###############################################################
#  Generated by:      Cadence Innovus 21.14-s109_1
#  OS:                Linux x86_64(Host ID caen-vnc-mi11.engin.umich.edu)
#  Generated on:      Sun Apr  2 18:51:28 2023
#  Design:            Main_controller
#  Command:           write_lef_abstract /afs/umich.edu/class/eecs627/w23/groups/group4/CNN_LSTM/Main_controller/apr/controller/data/Main_controller.lef -specifyTopLayer 4 -stripePin -PGpinLayers 4
###############################################################

VERSION 5.8 ;

BUSBITCHARS "[]" ;
DIVIDERCHAR "/" ;

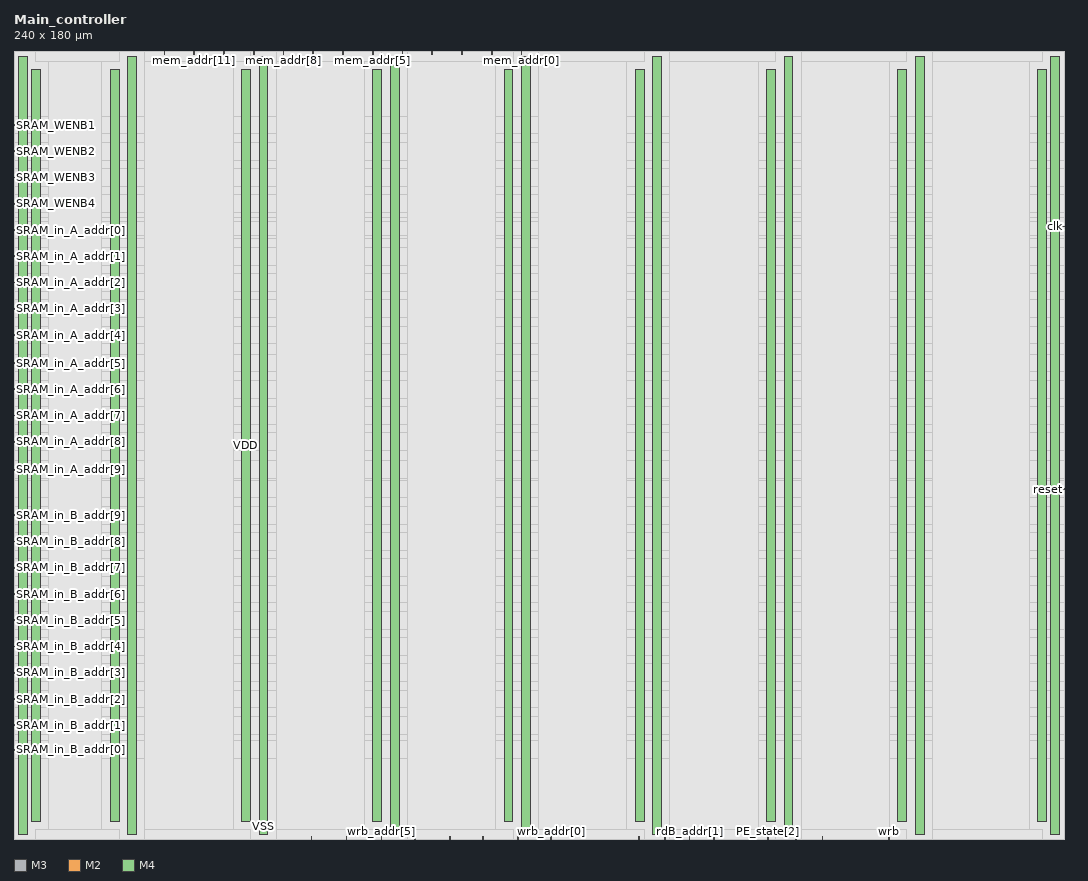
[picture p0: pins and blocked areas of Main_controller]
MACRO Main_controller
  CLASS BLOCK ;
  SIZE 240.000000 BY 180.000000 ;
  FOREIGN Main_controller 0.000000 0.000000 ;
  ORIGIN 0 0 ;
  SYMMETRY X Y R90 ;
  PIN clk
    DIRECTION INPUT ;
    USE SIGNAL ;
    ANTENNAPARTIALMETALAREA 7.46 LAYER M3  ;
    ANTENNAPARTIALMETALSIDEAREA 0.075 LAYER M3  ;
    ANTENNAMODEL OXIDE1 ;
    ANTENNAGATEAREA 0.8352 LAYER M3  ;
    ANTENNAMAXAREACAR 9.44732 LAYER M3  ;
    ANTENNAMAXSIDEAREACAR 0.0952826 LAYER M3  ;
    ANTENNAMAXCUTCAR 0.0957854 LAYER V3  ;
    PORT
      LAYER M3 ;
        RECT 239.400000 139.900000 240.000000 140.100000 ;
    END
  END clk
  PIN reset
    DIRECTION INPUT ;
    USE SIGNAL ;
    ANTENNAPARTIALMETALAREA 27.02 LAYER M3  ;
    ANTENNAPARTIALMETALSIDEAREA 0.2702 LAYER M3  ;
    ANTENNAPARTIALCUTAREA 0.04 LAYER V3  ;
    ANTENNAPARTIALMETALAREA 14.12 LAYER M4  ;
    ANTENNAPARTIALMETALSIDEAREA 0.1416 LAYER M4  ;
    ANTENNAMODEL OXIDE1 ;
    ANTENNAGATEAREA 1.932 LAYER M4  ;
    ANTENNAMAXAREACAR 25.2218 LAYER M4  ;
    ANTENNAMAXSIDEAREACAR 0.252442 LAYER M4  ;
    ANTENNAMAXCUTCAR 1.01838 LAYER V4  ;
    PORT
      LAYER M3 ;
        RECT 239.400000 79.900000 240.000000 80.100000 ;
    END
  END reset
  PIN wrb
    DIRECTION OUTPUT ;
    USE SIGNAL ;
    ANTENNAPARTIALMETALAREA 10.78 LAYER M2  ;
    ANTENNAPARTIALMETALSIDEAREA 0.1078 LAYER M2  ;
    ANTENNAPARTIALCUTAREA 0.08 LAYER V2  ;
    ANTENNAPARTIALMETALAREA 16.12 LAYER M3  ;
    ANTENNAPARTIALMETALSIDEAREA 0.1616 LAYER M3  ;
    ANTENNAPARTIALCUTAREA 0.04 LAYER V3  ;
    ANTENNADIFFAREA 2.014 LAYER M4  ;
    ANTENNAPARTIALMETALAREA 0.84 LAYER M4  ;
    ANTENNAPARTIALMETALSIDEAREA 0.0096 LAYER M4  ;
    ANTENNAMODEL OXIDE1 ;
    ANTENNAGATEAREA 0.2088 LAYER M4  ;
    ANTENNAMAXAREACAR 21.9899 LAYER M4  ;
    ANTENNAMAXSIDEAREACAR 0.229167 LAYER M4  ;
    ANTENNAMAXCUTCAR 2.87356 LAYER V4  ;
    PORT
      LAYER M2 ;
        RECT 199.900000 0.000000 200.100000 0.600000 ;
    END
  END wrb
  PIN PE_state[2]
    DIRECTION OUTPUT ;
    USE SIGNAL ;
    ANTENNAPARTIALMETALAREA 14.22 LAYER M2  ;
    ANTENNAPARTIALMETALSIDEAREA 0.1422 LAYER M2  ;
    ANTENNAPARTIALCUTAREA 0.08 LAYER V2  ;
    ANTENNADIFFAREA 2.172 LAYER M3  ;
    ANTENNAPARTIALMETALAREA 11.24 LAYER M3  ;
    ANTENNAPARTIALMETALSIDEAREA 0.1128 LAYER M3  ;
    PORT
      LAYER M2 ;
        RECT 172.300000 0.000000 172.500000 0.600000 ;
    END
  END PE_state[2]
  PIN PE_state[1]
    DIRECTION OUTPUT ;
    USE SIGNAL ;
    ANTENNAPARTIALMETALAREA 12.46 LAYER M2  ;
    ANTENNAPARTIALMETALSIDEAREA 0.1246 LAYER M2  ;
    ANTENNAPARTIALCUTAREA 0.08 LAYER V2  ;
    ANTENNADIFFAREA 3.196 LAYER M3  ;
    ANTENNAPARTIALMETALAREA 14.52 LAYER M3  ;
    ANTENNAPARTIALMETALSIDEAREA 0.1456 LAYER M3  ;
    PORT
      LAYER M2 ;
        RECT 178.700000 0.000000 178.900000 0.600000 ;
    END
  END PE_state[1]
  PIN PE_state[0]
    DIRECTION OUTPUT ;
    USE SIGNAL ;
    ANTENNAPARTIALMETALAREA 13.26 LAYER M2  ;
    ANTENNAPARTIALMETALSIDEAREA 0.1326 LAYER M2  ;
    ANTENNAPARTIALCUTAREA 0.08 LAYER V2  ;
    ANTENNADIFFAREA 3.378 LAYER M3  ;
    ANTENNAPARTIALMETALAREA 15.48 LAYER M3  ;
    ANTENNAPARTIALMETALSIDEAREA 0.1552 LAYER M3  ;
    PORT
      LAYER M2 ;
        RECT 184.700000 0.000000 184.900000 0.600000 ;
    END
  END PE_state[0]
  PIN wrb_addr[7]
    DIRECTION OUTPUT ;
    USE SIGNAL ;
    ANTENNAPARTIALMETALAREA 4.14 LAYER M2  ;
    ANTENNAPARTIALMETALSIDEAREA 0.0414 LAYER M2  ;
    ANTENNAPARTIALCUTAREA 0.08 LAYER V2  ;
    ANTENNADIFFAREA 2.014 LAYER M3  ;
    ANTENNAPARTIALMETALAREA 4 LAYER M3  ;
    ANTENNAPARTIALMETALSIDEAREA 0.0408 LAYER M3  ;
    ANTENNAMODEL OXIDE1 ;
    ANTENNAGATEAREA 0.4824 LAYER M3  ;
    ANTENNAMAXAREACAR 14.5562 LAYER M3  ;
    ANTENNAMAXSIDEAREACAR 0.153255 LAYER M3  ;
    ANTENNAMAXCUTCAR 1.72414 LAYER V3  ;
    PORT
      LAYER M2 ;
        RECT 67.900000 0.000000 68.100000 0.600000 ;
    END
  END wrb_addr[7]
  PIN wrb_addr[6]
    DIRECTION OUTPUT ;
    USE SIGNAL ;
    ANTENNAPARTIALMETALAREA 2.54 LAYER M2  ;
    ANTENNAPARTIALMETALSIDEAREA 0.0254 LAYER M2  ;
    ANTENNAPARTIALCUTAREA 0.08 LAYER V2  ;
    ANTENNADIFFAREA 2.014 LAYER M3  ;
    ANTENNAPARTIALMETALAREA 2.36 LAYER M3  ;
    ANTENNAPARTIALMETALSIDEAREA 0.024 LAYER M3  ;
    ANTENNAMODEL OXIDE1 ;
    ANTENNAGATEAREA 0.42 LAYER M3  ;
    ANTENNAMAXAREACAR 11.979 LAYER M3  ;
    ANTENNAMAXSIDEAREACAR 0.121749 LAYER M3  ;
    ANTENNAMAXCUTCAR 0.765189 LAYER V3  ;
    PORT
      LAYER M2 ;
        RECT 75.900000 0.000000 76.100000 0.600000 ;
    END
  END wrb_addr[6]
  PIN wrb_addr[5]
    DIRECTION OUTPUT ;
    USE SIGNAL ;
    ANTENNADIFFAREA 2.014 LAYER M2  ;
    ANTENNAPARTIALMETALAREA 4.32 LAYER M2  ;
    ANTENNAPARTIALMETALSIDEAREA 0.0432 LAYER M2  ;
    ANTENNAMODEL OXIDE1 ;
    ANTENNAGATEAREA 0.2136 LAYER M2  ;
    ANTENNAMAXAREACAR 20.7051 LAYER M2  ;
    ANTENNAMAXSIDEAREACAR 0.208333 LAYER M2  ;
    ANTENNAPARTIALCUTAREA 0.16 LAYER V2  ;
    ANTENNAMAXCUTCAR 0.93633 LAYER V2  ;
    ANTENNADIFFAREA 2.014 LAYER M3  ;
    ANTENNAPARTIALMETALAREA 1.52 LAYER M3  ;
    ANTENNAPARTIALMETALSIDEAREA 0.016 LAYER M3  ;
    ANTENNAGATEAREA 0.4464 LAYER M3  ;
    ANTENNAMAXAREACAR 24.1101 LAYER M3  ;
    ANTENNAMAXSIDEAREACAR 0.244176 LAYER M3  ;
    ANTENNAMAXCUTCAR 1.72414 LAYER V3  ;
    PORT
      LAYER M2 ;
        RECT 83.900000 0.000000 84.100000 0.600000 ;
    END
  END wrb_addr[5]
  PIN wrb_addr[4]
    DIRECTION OUTPUT ;
    USE SIGNAL ;
    ANTENNAPARTIALMETALAREA 1.82 LAYER M2  ;
    ANTENNAPARTIALMETALSIDEAREA 0.0182 LAYER M2  ;
    ANTENNAMODEL OXIDE1 ;
    ANTENNAGATEAREA 0.132 LAYER M2  ;
    ANTENNAMAXAREACAR 15.0939 LAYER M2  ;
    ANTENNAMAXSIDEAREACAR 0.151364 LAYER M2  ;
    ANTENNAPARTIALCUTAREA 0.08 LAYER V2  ;
    ANTENNAMAXCUTCAR 0.909091 LAYER V2  ;
    ANTENNAPARTIALMETALAREA 2.48 LAYER M3  ;
    ANTENNAPARTIALMETALSIDEAREA 0.0256 LAYER M3  ;
    ANTENNAGATEAREA 0.2952 LAYER M3  ;
    ANTENNAMAXAREACAR 23.495 LAYER M3  ;
    ANTENNAMAXSIDEAREACAR 0.238085 LAYER M3  ;
    ANTENNAPARTIALCUTAREA 0.08 LAYER V3  ;
    ANTENNAMAXCUTCAR 1.49649 LAYER V3  ;
    ANTENNADIFFAREA 2.014 LAYER M4  ;
    ANTENNAPARTIALMETALAREA 1.24 LAYER M4  ;
    ANTENNAPARTIALMETALSIDEAREA 0.0128 LAYER M4  ;
    ANTENNAGATEAREA 0.5208 LAYER M4  ;
    ANTENNAMAXAREACAR 25.876 LAYER M4  ;
    ANTENNAMAXSIDEAREACAR 0.262662 LAYER M4  ;
    ANTENNAMAXCUTCAR 1.63854 LAYER V4  ;
    PORT
      LAYER M2 ;
        RECT 91.500000 0.000000 91.700000 0.600000 ;
    END
  END wrb_addr[4]
  PIN wrb_addr[3]
    DIRECTION OUTPUT ;
    USE SIGNAL ;
    ANTENNAPARTIALMETALAREA 3.58 LAYER M2  ;
    ANTENNAPARTIALMETALSIDEAREA 0.0358 LAYER M2  ;
    ANTENNAMODEL OXIDE1 ;
    ANTENNAGATEAREA 0.0696 LAYER M2  ;
    ANTENNAMAXAREACAR 53.6782 LAYER M2  ;
    ANTENNAMAXSIDEAREACAR 0.537069 LAYER M2  ;
    ANTENNAPARTIALCUTAREA 0.08 LAYER V2  ;
    ANTENNAMAXCUTCAR 1.72414 LAYER V2  ;
    ANTENNADIFFAREA 2.014 LAYER M3  ;
    ANTENNAPARTIALMETALAREA 2.04 LAYER M3  ;
    ANTENNAPARTIALMETALSIDEAREA 0.0208 LAYER M3  ;
    ANTENNAGATEAREA 0.4152 LAYER M3  ;
    ANTENNAMAXAREACAR 58.5915 LAYER M3  ;
    ANTENNAMAXSIDEAREACAR 0.587165 LAYER M3  ;
    ANTENNAPARTIALCUTAREA 0.08 LAYER V3  ;
    ANTENNAMAXCUTCAR 1.91682 LAYER V3  ;
    ANTENNADIFFAREA 2.014 LAYER M4  ;
    ANTENNAPARTIALMETALAREA 2.44 LAYER M4  ;
    ANTENNAPARTIALMETALSIDEAREA 0.0248 LAYER M4  ;
    ANTENNAGATEAREA 0.684 LAYER M4  ;
    ANTENNAMAXAREACAR 62.1587 LAYER M4  ;
    ANTENNAMAXSIDEAREACAR 0.623423 LAYER M4  ;
    ANTENNAMAXCUTCAR 1.91682 LAYER V4  ;
    PORT
      LAYER M2 ;
        RECT 99.500000 0.000000 99.700000 0.600000 ;
    END
  END wrb_addr[3]
  PIN wrb_addr[2]
    DIRECTION OUTPUT ;
    USE SIGNAL ;
    ANTENNAPARTIALMETALAREA 2.46 LAYER M2  ;
    ANTENNAPARTIALMETALSIDEAREA 0.0246 LAYER M2  ;
    ANTENNAPARTIALCUTAREA 0.08 LAYER V2  ;
    ANTENNADIFFAREA 2.014 LAYER M3  ;
    ANTENNAPARTIALMETALAREA 1.8 LAYER M3  ;
    ANTENNAPARTIALMETALSIDEAREA 0.0184 LAYER M3  ;
    ANTENNAMODEL OXIDE1 ;
    ANTENNAGATEAREA 0.4392 LAYER M3  ;
    ANTENNAMAXAREACAR 14.0163 LAYER M3  ;
    ANTENNAMAXSIDEAREACAR 0.144202 LAYER M3  ;
    ANTENNAMAXCUTCAR 0.857199 LAYER V3  ;
    PORT
      LAYER M2 ;
        RECT 107.100000 0.000000 107.300000 0.600000 ;
    END
  END wrb_addr[2]
  PIN wrb_addr[1]
    DIRECTION OUTPUT ;
    USE SIGNAL ;
    ANTENNAPARTIALMETALAREA 2.7 LAYER M2  ;
    ANTENNAPARTIALMETALSIDEAREA 0.027 LAYER M2  ;
    ANTENNAPARTIALCUTAREA 0.08 LAYER V2  ;
    ANTENNADIFFAREA 2.014 LAYER M3  ;
    ANTENNAPARTIALMETALAREA 2.96 LAYER M3  ;
    ANTENNAPARTIALMETALSIDEAREA 0.0304 LAYER M3  ;
    ANTENNAMODEL OXIDE1 ;
    ANTENNAGATEAREA 0.3336 LAYER M3  ;
    ANTENNAMAXAREACAR 13.3925 LAYER M3  ;
    ANTENNAMAXSIDEAREACAR 0.137809 LAYER M3  ;
    ANTENNAMAXCUTCAR 0.814521 LAYER V3  ;
    PORT
      LAYER M2 ;
        RECT 115.100000 0.000000 115.300000 0.600000 ;
    END
  END wrb_addr[1]
  PIN wrb_addr[0]
    DIRECTION OUTPUT ;
    USE SIGNAL ;
    ANTENNAPARTIALMETALAREA 4.06 LAYER M2  ;
    ANTENNAPARTIALMETALSIDEAREA 0.0406 LAYER M2  ;
    ANTENNAPARTIALCUTAREA 0.08 LAYER V2  ;
    ANTENNADIFFAREA 2.014 LAYER M3  ;
    ANTENNAPARTIALMETALAREA 7.68 LAYER M3  ;
    ANTENNAPARTIALMETALSIDEAREA 0.0776 LAYER M3  ;
    ANTENNAMODEL OXIDE1 ;
    ANTENNAGATEAREA 0.2256 LAYER M3  ;
    ANTENNAMAXAREACAR 52.2724 LAYER M3  ;
    ANTENNAMAXSIDEAREACAR 0.532477 LAYER M3  ;
    ANTENNAPARTIALCUTAREA 0.08 LAYER V3  ;
    ANTENNAMAXCUTCAR 2.65346 LAYER V3  ;
    ANTENNADIFFAREA 2.014 LAYER M4  ;
    ANTENNAPARTIALMETALAREA 0.92 LAYER M4  ;
    ANTENNAPARTIALMETALSIDEAREA 0.0096 LAYER M4  ;
    ANTENNAGATEAREA 0.5616 LAYER M4  ;
    ANTENNAMAXAREACAR 53.9106 LAYER M4  ;
    ANTENNAMAXSIDEAREACAR 0.549571 LAYER M4  ;
    ANTENNAMAXCUTCAR 2.65346 LAYER V4  ;
    PORT
      LAYER M2 ;
        RECT 122.700000 0.000000 122.900000 0.600000 ;
    END
  END wrb_addr[0]
  PIN rdB_addr[3]
    DIRECTION OUTPUT ;
    USE SIGNAL ;
    ANTENNAPARTIALMETALAREA 1.26 LAYER M2  ;
    ANTENNAPARTIALMETALSIDEAREA 0.0126 LAYER M2  ;
    ANTENNAPARTIALCUTAREA 0.08 LAYER V2  ;
    ANTENNADIFFAREA 3.75 LAYER M3  ;
    ANTENNAPARTIALMETALAREA 8 LAYER M3  ;
    ANTENNAPARTIALMETALSIDEAREA 0.0808 LAYER M3  ;
    PORT
      LAYER M2 ;
        RECT 142.700000 0.000000 142.900000 0.600000 ;
    END
  END rdB_addr[3]
  PIN rdB_addr[2]
    DIRECTION OUTPUT ;
    USE SIGNAL ;
    ANTENNAPARTIALMETALAREA 5.74 LAYER M2  ;
    ANTENNAPARTIALMETALSIDEAREA 0.0574 LAYER M2  ;
    ANTENNAPARTIALCUTAREA 0.08 LAYER V2  ;
    ANTENNADIFFAREA 2.56 LAYER M3  ;
    ANTENNAPARTIALMETALAREA 5.48 LAYER M3  ;
    ANTENNAPARTIALMETALSIDEAREA 0.0552 LAYER M3  ;
    PORT
      LAYER M2 ;
        RECT 148.700000 0.000000 148.900000 0.600000 ;
    END
  END rdB_addr[2]
  PIN rdB_addr[1]
    DIRECTION OUTPUT ;
    USE SIGNAL ;
    ANTENNAPARTIALMETALAREA 8.3 LAYER M2  ;
    ANTENNAPARTIALMETALSIDEAREA 0.083 LAYER M2  ;
    ANTENNAPARTIALCUTAREA 0.08 LAYER V2  ;
    ANTENNADIFFAREA 8.58 LAYER M3  ;
    ANTENNAPARTIALMETALAREA 8.16 LAYER M3  ;
    ANTENNAPARTIALMETALSIDEAREA 0.0824 LAYER M3  ;
    ANTENNAMODEL OXIDE1 ;
    ANTENNAGATEAREA 0.4848 LAYER M3  ;
    ANTENNAMAXAREACAR 20.087 LAYER M3  ;
    ANTENNAMAXSIDEAREACAR 0.209418 LAYER M3  ;
    ANTENNAMAXCUTCAR 0.632911 LAYER V3  ;
    PORT
      LAYER M2 ;
        RECT 154.300000 0.000000 154.500000 0.600000 ;
    END
  END rdB_addr[1]
  PIN rdB_addr[0]
    DIRECTION OUTPUT ;
    USE SIGNAL ;
    ANTENNAPARTIALMETALAREA 8.62 LAYER M2  ;
    ANTENNAPARTIALMETALSIDEAREA 0.0862 LAYER M2  ;
    ANTENNAPARTIALCUTAREA 0.08 LAYER V2  ;
    ANTENNADIFFAREA 2.112 LAYER M3  ;
    ANTENNAPARTIALMETALAREA 13.92 LAYER M3  ;
    ANTENNAPARTIALMETALSIDEAREA 0.1408 LAYER M3  ;
    ANTENNAMODEL OXIDE1 ;
    ANTENNAGATEAREA 0.7488 LAYER M3  ;
    ANTENNAMAXAREACAR 46.7611 LAYER M3  ;
    ANTENNAMAXSIDEAREACAR 0.47298 LAYER M3  ;
    ANTENNAMAXCUTCAR 1.34409 LAYER V3  ;
    PORT
      LAYER M2 ;
        RECT 159.900000 0.000000 160.100000 0.600000 ;
    END
  END rdB_addr[0]
  PIN mem_addr[12]
    DIRECTION OUTPUT ;
    USE SIGNAL ;
    ANTENNAPARTIALMETALAREA 1.34 LAYER M2  ;
    ANTENNAPARTIALMETALSIDEAREA 0.0134 LAYER M2  ;
    ANTENNAPARTIALCUTAREA 0.08 LAYER V2  ;
    ANTENNADIFFAREA 2.014 LAYER M3  ;
    ANTENNAPARTIALMETALAREA 1.04 LAYER M3  ;
    ANTENNAPARTIALMETALSIDEAREA 0.0112 LAYER M3  ;
    ANTENNAMODEL OXIDE1 ;
    ANTENNAGATEAREA 0.2016 LAYER M3  ;
    ANTENNAMAXAREACAR 20.3303 LAYER M3  ;
    ANTENNAMAXSIDEAREACAR 0.209715 LAYER M3  ;
    ANTENNAMAXCUTCAR 1.94308 LAYER V3  ;
    PORT
      LAYER M2 ;
        RECT 34.300000 179.400000 34.500000 180.000000 ;
    END
  END mem_addr[12]
  PIN mem_addr[11]
    DIRECTION OUTPUT ;
    USE SIGNAL ;
    ANTENNAPARTIALMETALAREA 4.94 LAYER M2  ;
    ANTENNAPARTIALMETALSIDEAREA 0.0494 LAYER M2  ;
    ANTENNAMODEL OXIDE1 ;
    ANTENNAGATEAREA 0.2016 LAYER M2  ;
    ANTENNAMAXAREACAR 28.366 LAYER M2  ;
    ANTENNAMAXSIDEAREACAR 0.28412 LAYER M2  ;
    ANTENNAPARTIALCUTAREA 0.08 LAYER V2  ;
    ANTENNAMAXCUTCAR 1.54625 LAYER V2  ;
    ANTENNADIFFAREA 2.014 LAYER M3  ;
    ANTENNAPARTIALMETALAREA 0.76 LAYER M3  ;
    ANTENNAPARTIALMETALSIDEAREA 0.008 LAYER M3  ;
    ANTENNAGATEAREA 0.2016 LAYER M3  ;
    ANTENNAMAXAREACAR 32.1359 LAYER M3  ;
    ANTENNAMAXSIDEAREACAR 0.323803 LAYER M3  ;
    ANTENNAMAXCUTCAR 1.54625 LAYER V3  ;
    PORT
      LAYER M2 ;
        RECT 41.100000 179.400000 41.300000 180.000000 ;
    END
  END mem_addr[11]
  PIN mem_addr[10]
    DIRECTION OUTPUT ;
    USE SIGNAL ;
    ANTENNAPARTIALMETALAREA 2.96 LAYER M2  ;
    ANTENNAPARTIALMETALSIDEAREA 0.0296 LAYER M2  ;
    ANTENNAMODEL OXIDE1 ;
    ANTENNAGATEAREA 0.2808 LAYER M2  ;
    ANTENNAMAXAREACAR 12.5393 LAYER M2  ;
    ANTENNAMAXSIDEAREACAR 0.124365 LAYER M2  ;
    ANTENNAPARTIALCUTAREA 0.08 LAYER V2  ;
    ANTENNAMAXCUTCAR 0.822535 LAYER V2  ;
    ANTENNADIFFAREA 2.014 LAYER M3  ;
    ANTENNAPARTIALMETALAREA 0.88 LAYER M3  ;
    ANTENNAPARTIALMETALSIDEAREA 0.0096 LAYER M3  ;
    ANTENNAGATEAREA 0.3504 LAYER M3  ;
    ANTENNAMAXAREACAR 26.4884 LAYER M3  ;
    ANTENNAMAXSIDEAREACAR 0.273374 LAYER M3  ;
    ANTENNAMAXCUTCAR 3.44828 LAYER V3  ;
    PORT
      LAYER M2 ;
        RECT 47.900000 179.400000 48.100000 180.000000 ;
    END
  END mem_addr[10]
  PIN mem_addr[9]
    DIRECTION OUTPUT ;
    USE SIGNAL ;
    ANTENNAPARTIALMETALAREA 4.3 LAYER M2  ;
    ANTENNAPARTIALMETALSIDEAREA 0.043 LAYER M2  ;
    ANTENNAMODEL OXIDE1 ;
    ANTENNAGATEAREA 0.2808 LAYER M2  ;
    ANTENNAMAXAREACAR 17.3114 LAYER M2  ;
    ANTENNAMAXSIDEAREACAR 0.172086 LAYER M2  ;
    ANTENNAPARTIALCUTAREA 0.08 LAYER V2  ;
    ANTENNAMAXCUTCAR 0.822535 LAYER V2  ;
    ANTENNADIFFAREA 2.014 LAYER M3  ;
    ANTENNAPARTIALMETALAREA 1.04 LAYER M3  ;
    ANTENNAPARTIALMETALSIDEAREA 0.0112 LAYER M3  ;
    ANTENNAGATEAREA 0.3504 LAYER M3  ;
    ANTENNAMAXAREACAR 33.8416 LAYER M3  ;
    ANTENNAMAXSIDEAREACAR 0.346906 LAYER M3  ;
    ANTENNAMAXCUTCAR 3.44828 LAYER V3  ;
    PORT
      LAYER M2 ;
        RECT 54.700000 179.400000 54.900000 180.000000 ;
    END
  END mem_addr[9]
  PIN mem_addr[8]
    DIRECTION OUTPUT ;
    USE SIGNAL ;
    ANTENNAPARTIALMETALAREA 1.66 LAYER M2  ;
    ANTENNAPARTIALMETALSIDEAREA 0.0166 LAYER M2  ;
    ANTENNAPARTIALCUTAREA 0.08 LAYER V2  ;
    ANTENNADIFFAREA 2.014 LAYER M3  ;
    ANTENNAPARTIALMETALAREA 2.16 LAYER M3  ;
    ANTENNAPARTIALMETALSIDEAREA 0.0224 LAYER M3  ;
    ANTENNAMODEL OXIDE1 ;
    ANTENNAGATEAREA 0.5808 LAYER M3  ;
    ANTENNAMAXAREACAR 22.1148 LAYER M3  ;
    ANTENNAMAXSIDEAREACAR 0.224186 LAYER M3  ;
    ANTENNAMAXCUTCAR 2.29885 LAYER V3  ;
    PORT
      LAYER M2 ;
        RECT 61.500000 179.400000 61.700000 180.000000 ;
    END
  END mem_addr[8]
  PIN mem_addr[7]
    DIRECTION OUTPUT ;
    USE SIGNAL ;
    ANTENNAPARTIALMETALAREA 2.3 LAYER M2  ;
    ANTENNAPARTIALMETALSIDEAREA 0.023 LAYER M2  ;
    ANTENNAPARTIALCUTAREA 0.08 LAYER V2  ;
    ANTENNADIFFAREA 2.014 LAYER M3  ;
    ANTENNAPARTIALMETALAREA 2.28 LAYER M3  ;
    ANTENNAPARTIALMETALSIDEAREA 0.024 LAYER M3  ;
    ANTENNAMODEL OXIDE1 ;
    ANTENNAGATEAREA 0.3504 LAYER M3  ;
    ANTENNAMAXAREACAR 16.6908 LAYER M3  ;
    ANTENNAMAXSIDEAREACAR 0.176539 LAYER M3  ;
    ANTENNAMAXCUTCAR 3.44828 LAYER V3  ;
    PORT
      LAYER M2 ;
        RECT 68.300000 179.400000 68.500000 180.000000 ;
    END
  END mem_addr[7]
  PIN mem_addr[6]
    DIRECTION OUTPUT ;
    USE SIGNAL ;
    ANTENNAPARTIALMETALAREA 2.38 LAYER M2  ;
    ANTENNAPARTIALMETALSIDEAREA 0.0238 LAYER M2  ;
    ANTENNAPARTIALCUTAREA 0.08 LAYER V2  ;
    ANTENNADIFFAREA 2.014 LAYER M3  ;
    ANTENNAPARTIALMETALAREA 3.8 LAYER M3  ;
    ANTENNAPARTIALMETALSIDEAREA 0.0392 LAYER M3  ;
    ANTENNAMODEL OXIDE1 ;
    ANTENNAGATEAREA 0.4992 LAYER M3  ;
    ANTENNAMAXAREACAR 20.4567 LAYER M3  ;
    ANTENNAMAXSIDEAREACAR 0.20882 LAYER M3  ;
    ANTENNAMAXCUTCAR 2.29885 LAYER V3  ;
    PORT
      LAYER M2 ;
        RECT 75.100000 179.400000 75.300000 180.000000 ;
    END
  END mem_addr[6]
  PIN mem_addr[5]
    DIRECTION OUTPUT ;
    USE SIGNAL ;
    ANTENNAPARTIALMETALAREA 1.98 LAYER M2  ;
    ANTENNAPARTIALMETALSIDEAREA 0.0198 LAYER M2  ;
    ANTENNAMODEL OXIDE1 ;
    ANTENNAGATEAREA 0.1488 LAYER M2  ;
    ANTENNAMAXAREACAR 15.3044 LAYER M2  ;
    ANTENNAMAXSIDEAREACAR 0.152016 LAYER M2  ;
    ANTENNAPARTIALCUTAREA 0.08 LAYER V2  ;
    ANTENNAMAXCUTCAR 1.07527 LAYER V2  ;
    ANTENNADIFFAREA 2.014 LAYER M3  ;
    ANTENNAPARTIALMETALAREA 3.44 LAYER M3  ;
    ANTENNAPARTIALMETALSIDEAREA 0.0352 LAYER M3  ;
    ANTENNAGATEAREA 0.3504 LAYER M3  ;
    ANTENNAMAXAREACAR 47.5875 LAYER M3  ;
    ANTENNAMAXSIDEAREACAR 0.484365 LAYER M3  ;
    ANTENNAMAXCUTCAR 3.44828 LAYER V3  ;
    PORT
      LAYER M2 ;
        RECT 81.900000 179.400000 82.100000 180.000000 ;
    END
  END mem_addr[5]
  PIN mem_addr[4]
    DIRECTION OUTPUT ;
    USE SIGNAL ;
    ANTENNAPARTIALMETALAREA 1.34 LAYER M2  ;
    ANTENNAPARTIALMETALSIDEAREA 0.0134 LAYER M2  ;
    ANTENNAPARTIALCUTAREA 0.08 LAYER V2  ;
    ANTENNADIFFAREA 2.014 LAYER M3  ;
    ANTENNAPARTIALMETALAREA 2.92 LAYER M3  ;
    ANTENNAPARTIALMETALSIDEAREA 0.0304 LAYER M3  ;
    ANTENNAMODEL OXIDE1 ;
    ANTENNAGATEAREA 0.432 LAYER M3  ;
    ANTENNAMAXAREACAR 34.393 LAYER M3  ;
    ANTENNAMAXSIDEAREACAR 0.34994 LAYER M3  ;
    ANTENNAMAXCUTCAR 2.29885 LAYER V3  ;
    PORT
      LAYER M2 ;
        RECT 88.700000 179.400000 88.900000 180.000000 ;
    END
  END mem_addr[4]
  PIN mem_addr[3]
    DIRECTION OUTPUT ;
    USE SIGNAL ;
    ANTENNAPARTIALMETALAREA 1.34 LAYER M2  ;
    ANTENNAPARTIALMETALSIDEAREA 0.0134 LAYER M2  ;
    ANTENNAPARTIALCUTAREA 0.08 LAYER V2  ;
    ANTENNADIFFAREA 2.014 LAYER M3  ;
    ANTENNAPARTIALMETALAREA 1.28 LAYER M3  ;
    ANTENNAPARTIALMETALSIDEAREA 0.0136 LAYER M3  ;
    ANTENNAMODEL OXIDE1 ;
    ANTENNAGATEAREA 0.3504 LAYER M3  ;
    ANTENNAMAXAREACAR 18.0441 LAYER M3  ;
    ANTENNAMAXSIDEAREACAR 0.183121 LAYER M3  ;
    ANTENNAMAXCUTCAR 2.29885 LAYER V3  ;
    PORT
      LAYER M2 ;
        RECT 95.500000 179.400000 95.700000 180.000000 ;
    END
  END mem_addr[3]
  PIN mem_addr[2]
    DIRECTION OUTPUT ;
    USE SIGNAL ;
    ANTENNAPARTIALMETALAREA 1.98 LAYER M2  ;
    ANTENNAPARTIALMETALSIDEAREA 0.0198 LAYER M2  ;
    ANTENNAPARTIALCUTAREA 0.08 LAYER V2  ;
    ANTENNADIFFAREA 2.014 LAYER M3  ;
    ANTENNAPARTIALMETALAREA 2.68 LAYER M3  ;
    ANTENNAPARTIALMETALSIDEAREA 0.028 LAYER M3  ;
    ANTENNAMODEL OXIDE1 ;
    ANTENNAGATEAREA 0.4992 LAYER M3  ;
    ANTENNAMAXAREACAR 32.7939 LAYER M3  ;
    ANTENNAMAXSIDEAREACAR 0.33655 LAYER M3  ;
    ANTENNAMAXCUTCAR 3.44828 LAYER V3  ;
    PORT
      LAYER M2 ;
        RECT 102.300000 179.400000 102.500000 180.000000 ;
    END
  END mem_addr[2]
  PIN mem_addr[1]
    DIRECTION OUTPUT ;
    USE SIGNAL ;
    ANTENNAPARTIALMETALAREA 2.3 LAYER M2  ;
    ANTENNAPARTIALMETALSIDEAREA 0.023 LAYER M2  ;
    ANTENNAMODEL OXIDE1 ;
    ANTENNAGATEAREA 0.1488 LAYER M2  ;
    ANTENNAMAXAREACAR 16.4778 LAYER M2  ;
    ANTENNAMAXSIDEAREACAR 0.165323 LAYER M2  ;
    ANTENNAPARTIALCUTAREA 0.08 LAYER V2  ;
    ANTENNAMAXCUTCAR 0.806452 LAYER V2  ;
    ANTENNADIFFAREA 2.014 LAYER M3  ;
    ANTENNAPARTIALMETALAREA 2.08 LAYER M3  ;
    ANTENNAPARTIALMETALSIDEAREA 0.0216 LAYER M3  ;
    ANTENNAGATEAREA 0.3504 LAYER M3  ;
    ANTENNAMAXAREACAR 36.8096 LAYER M3  ;
    ANTENNAMAXSIDEAREACAR 0.376586 LAYER M3  ;
    ANTENNAMAXCUTCAR 3.44828 LAYER V3  ;
    PORT
      LAYER M2 ;
        RECT 109.100000 179.400000 109.300000 180.000000 ;
    END
  END mem_addr[1]
  PIN mem_addr[0]
    DIRECTION OUTPUT ;
    USE SIGNAL ;
    ANTENNAPARTIALMETALAREA 1.66 LAYER M2  ;
    ANTENNAPARTIALMETALSIDEAREA 0.0166 LAYER M2  ;
    ANTENNAPARTIALCUTAREA 0.08 LAYER V2  ;
    ANTENNAPARTIALMETALAREA 2.04 LAYER M3  ;
    ANTENNAPARTIALMETALSIDEAREA 0.0208 LAYER M3  ;
    ANTENNAMODEL OXIDE1 ;
    ANTENNAGATEAREA 0.1488 LAYER M3  ;
    ANTENNAMAXAREACAR 17.5894 LAYER M3  ;
    ANTENNAMAXSIDEAREACAR 0.180242 LAYER M3  ;
    ANTENNAPARTIALCUTAREA 0.08 LAYER V3  ;
    ANTENNAMAXCUTCAR 1.6129 LAYER V3  ;
    ANTENNADIFFAREA 2.014 LAYER M4  ;
    ANTENNAPARTIALMETALAREA 3.48 LAYER M4  ;
    ANTENNAPARTIALMETALSIDEAREA 0.0352 LAYER M4  ;
    ANTENNAGATEAREA 0.504 LAYER M4  ;
    ANTENNAMAXAREACAR 24.4941 LAYER M4  ;
    ANTENNAMAXSIDEAREACAR 0.250083 LAYER M4  ;
    ANTENNAMAXCUTCAR 2.52408 LAYER V4  ;
    PORT
      LAYER M2 ;
        RECT 115.900000 179.400000 116.100000 180.000000 ;
    END
  END mem_addr[0]
  PIN SRAM_in_A_addr[9]
    DIRECTION OUTPUT ;
    USE SIGNAL ;
    ANTENNADIFFAREA 2.014 LAYER M3  ;
    ANTENNAPARTIALMETALAREA 9.02 LAYER M3  ;
    ANTENNAPARTIALMETALSIDEAREA 0.0918 LAYER M3  ;
    ANTENNAMODEL OXIDE1 ;
    ANTENNAGATEAREA 0.6648 LAYER M3  ;
    ANTENNAMAXAREACAR 32.6225 LAYER M3  ;
    ANTENNAMAXSIDEAREACAR 0.330814 LAYER M3  ;
    ANTENNAMAXCUTCAR 2.12121 LAYER V3  ;
    PORT
      LAYER M3 ;
        RECT 0.000000 84.300000 0.600000 84.500000 ;
    END
  END SRAM_in_A_addr[9]
  PIN SRAM_in_A_addr[8]
    DIRECTION OUTPUT ;
    USE SIGNAL ;
    ANTENNADIFFAREA 2.014 LAYER M3  ;
    ANTENNAPARTIALMETALAREA 9.22 LAYER M3  ;
    ANTENNAPARTIALMETALSIDEAREA 0.0934 LAYER M3  ;
    ANTENNAMODEL OXIDE1 ;
    ANTENNAGATEAREA 0.6144 LAYER M3  ;
    ANTENNAMAXAREACAR 27.3121 LAYER M3  ;
    ANTENNAMAXSIDEAREACAR 0.272852 LAYER M3  ;
    ANTENNAMAXCUTCAR 1.14943 LAYER V3  ;
    PORT
      LAYER M3 ;
        RECT 0.000000 90.700000 0.600000 90.900000 ;
    END
  END SRAM_in_A_addr[8]
  PIN SRAM_in_A_addr[7]
    DIRECTION OUTPUT ;
    USE SIGNAL ;
    ANTENNAPARTIALMETALAREA 12.06 LAYER M3  ;
    ANTENNAPARTIALMETALSIDEAREA 0.1206 LAYER M3  ;
    ANTENNAMODEL OXIDE1 ;
    ANTENNAGATEAREA 0.4752 LAYER M3  ;
    ANTENNAMAXAREACAR 30.8714 LAYER M3  ;
    ANTENNAMAXSIDEAREACAR 0.310374 LAYER M3  ;
    ANTENNAPARTIALCUTAREA 0.08 LAYER V3  ;
    ANTENNAMAXCUTCAR 1.24362 LAYER V3  ;
    ANTENNADIFFAREA 4.168 LAYER M4  ;
    ANTENNAPARTIALMETALAREA 3.64 LAYER M4  ;
    ANTENNAPARTIALMETALSIDEAREA 0.0368 LAYER M4  ;
    ANTENNAGATEAREA 1.3176 LAYER M4  ;
    ANTENNAMAXAREACAR 33.634 LAYER M4  ;
    ANTENNAMAXSIDEAREACAR 0.338303 LAYER M4  ;
    ANTENNAMAXCUTCAR 1.53568 LAYER V4  ;
    PORT
      LAYER M3 ;
        RECT 0.000000 96.700000 0.600000 96.900000 ;
    END
  END SRAM_in_A_addr[7]
  PIN SRAM_in_A_addr[6]
    DIRECTION OUTPUT ;
    USE SIGNAL ;
    ANTENNAPARTIALMETALAREA 4.94 LAYER M3  ;
    ANTENNAPARTIALMETALSIDEAREA 0.0494 LAYER M3  ;
    ANTENNAPARTIALCUTAREA 0.08 LAYER V3  ;
    ANTENNADIFFAREA 4.168 LAYER M4  ;
    ANTENNAPARTIALMETALAREA 3.36 LAYER M4  ;
    ANTENNAPARTIALMETALSIDEAREA 0.0344 LAYER M4  ;
    ANTENNAMODEL OXIDE1 ;
    ANTENNAGATEAREA 1.4304 LAYER M4  ;
    ANTENNAMAXAREACAR 45.6146 LAYER M4  ;
    ANTENNAMAXSIDEAREACAR 0.464998 LAYER M4  ;
    ANTENNAMAXCUTCAR 2.9639 LAYER V4  ;
    PORT
      LAYER M3 ;
        RECT 0.000000 102.700000 0.600000 102.900000 ;
    END
  END SRAM_in_A_addr[6]
  PIN SRAM_in_A_addr[5]
    DIRECTION OUTPUT ;
    USE SIGNAL ;
    ANTENNAPARTIALMETALAREA 5.66 LAYER M3  ;
    ANTENNAPARTIALMETALSIDEAREA 0.0566 LAYER M3  ;
    ANTENNAPARTIALCUTAREA 0.08 LAYER V3  ;
    ANTENNADIFFAREA 3.996 LAYER M4  ;
    ANTENNAPARTIALMETALAREA 10.16 LAYER M4  ;
    ANTENNAPARTIALMETALSIDEAREA 0.1024 LAYER M4  ;
    ANTENNAMODEL OXIDE1 ;
    ANTENNAGATEAREA 2.0616 LAYER M4  ;
    ANTENNAMAXAREACAR 29.8738 LAYER M4  ;
    ANTENNAMAXSIDEAREACAR 0.307735 LAYER M4  ;
    ANTENNAMAXCUTCAR 1.96078 LAYER V4  ;
    PORT
      LAYER M3 ;
        RECT 0.000000 108.700000 0.600000 108.900000 ;
    END
  END SRAM_in_A_addr[5]
  PIN SRAM_in_A_addr[4]
    DIRECTION OUTPUT ;
    USE SIGNAL ;
    ANTENNADIFFAREA 2.014 LAYER M3  ;
    ANTENNAPARTIALMETALAREA 11.9 LAYER M3  ;
    ANTENNAPARTIALMETALSIDEAREA 0.119 LAYER M3  ;
    ANTENNAMODEL OXIDE1 ;
    ANTENNAGATEAREA 0.54 LAYER M3  ;
    ANTENNAMAXAREACAR 29.4508 LAYER M3  ;
    ANTENNAMAXSIDEAREACAR 0.300543 LAYER M3  ;
    ANTENNAMAXCUTCAR 1.72414 LAYER V3  ;
    PORT
      LAYER M3 ;
        RECT 0.000000 115.100000 0.600000 115.300000 ;
    END
  END SRAM_in_A_addr[4]
  PIN SRAM_in_A_addr[3]
    DIRECTION OUTPUT ;
    USE SIGNAL ;
    ANTENNADIFFAREA 4.168 LAYER M3  ;
    ANTENNAPARTIALMETALAREA 14.34 LAYER M3  ;
    ANTENNAPARTIALMETALSIDEAREA 0.1438 LAYER M3  ;
    ANTENNAMODEL OXIDE1 ;
    ANTENNAGATEAREA 0.624 LAYER M3  ;
    ANTENNAMAXAREACAR 30.3946 LAYER M3  ;
    ANTENNAMAXSIDEAREACAR 0.310621 LAYER M3  ;
    ANTENNAPARTIALCUTAREA 0.08 LAYER V3  ;
    ANTENNAMAXCUTCAR 1.85234 LAYER V3  ;
    ANTENNADIFFAREA 4.168 LAYER M4  ;
    ANTENNAPARTIALMETALAREA 0.76 LAYER M4  ;
    ANTENNAPARTIALMETALSIDEAREA 0.008 LAYER M4  ;
    ANTENNAGATEAREA 0.7824 LAYER M4  ;
    ANTENNAMAXAREACAR 31.3659 LAYER M4  ;
    ANTENNAMAXSIDEAREACAR 0.320846 LAYER M4  ;
    ANTENNAMAXCUTCAR 1.85234 LAYER V4  ;
    PORT
      LAYER M3 ;
        RECT 0.000000 121.100000 0.600000 121.300000 ;
    END
  END SRAM_in_A_addr[3]
  PIN SRAM_in_A_addr[2]
    DIRECTION OUTPUT ;
    USE SIGNAL ;
    ANTENNADIFFAREA 4.168 LAYER M3  ;
    ANTENNAPARTIALMETALAREA 14.9 LAYER M3  ;
    ANTENNAPARTIALMETALSIDEAREA 0.1502 LAYER M3  ;
    ANTENNAMODEL OXIDE1 ;
    ANTENNAGATEAREA 0.9312 LAYER M3  ;
    ANTENNAMAXAREACAR 23.1379 LAYER M3  ;
    ANTENNAMAXSIDEAREACAR 0.236171 LAYER M3  ;
    ANTENNAPARTIALCUTAREA 0.08 LAYER V3  ;
    ANTENNAMAXCUTCAR 2.00899 LAYER V3  ;
    ANTENNADIFFAREA 4.168 LAYER M4  ;
    ANTENNAPARTIALMETALAREA 9.64 LAYER M4  ;
    ANTENNAPARTIALMETALSIDEAREA 0.0968 LAYER M4  ;
    ANTENNAGATEAREA 1.2192 LAYER M4  ;
    ANTENNAMAXAREACAR 31.0447 LAYER M4  ;
    ANTENNAMAXSIDEAREACAR 0.315567 LAYER M4  ;
    ANTENNAMAXCUTCAR 2.65873 LAYER V4  ;
    PORT
      LAYER M3 ;
        RECT 0.000000 127.100000 0.600000 127.300000 ;
    END
  END SRAM_in_A_addr[2]
  PIN SRAM_in_A_addr[1]
    DIRECTION OUTPUT ;
    USE SIGNAL ;
    ANTENNADIFFAREA 4.168 LAYER M3  ;
    ANTENNAPARTIALMETALAREA 12.36 LAYER M3  ;
    ANTENNAPARTIALMETALSIDEAREA 0.124 LAYER M3  ;
    ANTENNAMODEL OXIDE1 ;
    ANTENNAGATEAREA 0.3912 LAYER M3  ;
    ANTENNAMAXAREACAR 42.5277 LAYER M3  ;
    ANTENNAMAXSIDEAREACAR 0.427609 LAYER M3  ;
    ANTENNAPARTIALCUTAREA 0.08 LAYER V3  ;
    ANTENNAMAXCUTCAR 0.983711 LAYER V3  ;
    ANTENNADIFFAREA 4.168 LAYER M4  ;
    ANTENNAPARTIALMETALAREA 2.24 LAYER M4  ;
    ANTENNAPARTIALMETALSIDEAREA 0.0232 LAYER M4  ;
    ANTENNAGATEAREA 1.3512 LAYER M4  ;
    ANTENNAMAXAREACAR 44.1855 LAYER M4  ;
    ANTENNAMAXSIDEAREACAR 0.444779 LAYER M4  ;
    ANTENNAMAXCUTCAR 1.46248 LAYER V4  ;
    PORT
      LAYER M3 ;
        RECT 0.000000 133.100000 0.600000 133.300000 ;
    END
  END SRAM_in_A_addr[1]
  PIN SRAM_in_A_addr[0]
    DIRECTION OUTPUT ;
    USE SIGNAL ;
    ANTENNAPARTIALMETALAREA 8.26 LAYER M3  ;
    ANTENNAPARTIALMETALSIDEAREA 0.083 LAYER M3  ;
    ANTENNAMODEL OXIDE1 ;
    ANTENNAGATEAREA 0.3216 LAYER M3  ;
    ANTENNAMAXAREACAR 31.8917 LAYER M3  ;
    ANTENNAMAXSIDEAREACAR 0.316867 LAYER M3  ;
    ANTENNAPARTIALCUTAREA 0.04 LAYER V3  ;
    ANTENNAMAXCUTCAR 0.641952 LAYER V3  ;
    ANTENNADIFFAREA 4.168 LAYER M4  ;
    ANTENNAPARTIALMETALAREA 5.24 LAYER M4  ;
    ANTENNAPARTIALMETALSIDEAREA 0.0528 LAYER M4  ;
    ANTENNAGATEAREA 1.2504 LAYER M4  ;
    ANTENNAMAXAREACAR 36.0823 LAYER M4  ;
    ANTENNAMAXSIDEAREACAR 0.359094 LAYER M4  ;
    ANTENNAMAXCUTCAR 1.31444 LAYER V4  ;
    PORT
      LAYER M3 ;
        RECT 0.000000 139.100000 0.600000 139.300000 ;
    END
  END SRAM_in_A_addr[0]
  PIN SRAM_in_B_addr[9]
    DIRECTION OUTPUT ;
    USE SIGNAL ;
    ANTENNAPARTIALMETALAREA 4.9 LAYER M3  ;
    ANTENNAPARTIALMETALSIDEAREA 0.0494 LAYER M3  ;
    ANTENNAMODEL OXIDE1 ;
    ANTENNAGATEAREA 0.5208 LAYER M3  ;
    ANTENNAMAXAREACAR 18.2374 LAYER M3  ;
    ANTENNAMAXSIDEAREACAR 0.180612 LAYER M3  ;
    ANTENNAPARTIALCUTAREA 0.08 LAYER V3  ;
    ANTENNAMAXCUTCAR 1.69207 LAYER V3  ;
    ANTENNADIFFAREA 2.014 LAYER M4  ;
    ANTENNAPARTIALMETALAREA 1.4 LAYER M4  ;
    ANTENNAPARTIALMETALSIDEAREA 0.0144 LAYER M4  ;
    ANTENNAGATEAREA 0.8016 LAYER M4  ;
    ANTENNAMAXAREACAR 19.9839 LAYER M4  ;
    ANTENNAMAXSIDEAREACAR 0.198576 LAYER M4  ;
    ANTENNAMAXCUTCAR 1.69207 LAYER V4  ;
    PORT
      LAYER M3 ;
        RECT 0.000000 73.900000 0.600000 74.100000 ;
    END
  END SRAM_in_B_addr[9]
  PIN SRAM_in_B_addr[8]
    DIRECTION OUTPUT ;
    USE SIGNAL ;
    ANTENNAPARTIALMETALAREA 4.86 LAYER M3  ;
    ANTENNAPARTIALMETALSIDEAREA 0.0486 LAYER M3  ;
    ANTENNAMODEL OXIDE1 ;
    ANTENNAGATEAREA 0.2328 LAYER M3  ;
    ANTENNAMAXAREACAR 27.4328 LAYER M3  ;
    ANTENNAMAXSIDEAREACAR 0.276357 LAYER M3  ;
    ANTENNAPARTIALCUTAREA 0.08 LAYER V3  ;
    ANTENNAMAXCUTCAR 1.46248 LAYER V3  ;
    ANTENNADIFFAREA 2.014 LAYER M4  ;
    ANTENNAPARTIALMETALAREA 2.2 LAYER M4  ;
    ANTENNAPARTIALMETALSIDEAREA 0.0224 LAYER M4  ;
    ANTENNAGATEAREA 0.5976 LAYER M4  ;
    ANTENNAMAXAREACAR 31.1142 LAYER M4  ;
    ANTENNAMAXSIDEAREACAR 0.31384 LAYER M4  ;
    ANTENNAMAXCUTCAR 1.94344 LAYER V4  ;
    PORT
      LAYER M3 ;
        RECT 0.000000 67.900000 0.600000 68.100000 ;
    END
  END SRAM_in_B_addr[8]
  PIN SRAM_in_B_addr[7]
    DIRECTION OUTPUT ;
    USE SIGNAL ;
    ANTENNADIFFAREA 2.014 LAYER M3  ;
    ANTENNAPARTIALMETALAREA 5.22 LAYER M3  ;
    ANTENNAPARTIALMETALSIDEAREA 0.0526 LAYER M3  ;
    ANTENNAMODEL OXIDE1 ;
    ANTENNAGATEAREA 0.6528 LAYER M3  ;
    ANTENNAMAXAREACAR 20.3543 LAYER M3  ;
    ANTENNAMAXSIDEAREACAR 0.208662 LAYER M3  ;
    ANTENNAPARTIALCUTAREA 0.08 LAYER V3  ;
    ANTENNAMAXCUTCAR 1.6377 LAYER V3  ;
    ANTENNADIFFAREA 2.014 LAYER M4  ;
    ANTENNAPARTIALMETALAREA 1 LAYER M4  ;
    ANTENNAPARTIALMETALSIDEAREA 0.0104 LAYER M4  ;
    ANTENNAGATEAREA 0.7224 LAYER M4  ;
    ANTENNAMAXAREACAR 21.7386 LAYER M4  ;
    ANTENNAMAXSIDEAREACAR 0.223059 LAYER M4  ;
    ANTENNAMAXCUTCAR 3.44828 LAYER V4  ;
    PORT
      LAYER M3 ;
        RECT 0.000000 61.900000 0.600000 62.100000 ;
    END
  END SRAM_in_B_addr[7]
  PIN SRAM_in_B_addr[6]
    DIRECTION OUTPUT ;
    USE SIGNAL ;
    ANTENNADIFFAREA 2.014 LAYER M3  ;
    ANTENNAPARTIALMETALAREA 7.42 LAYER M3  ;
    ANTENNAPARTIALMETALSIDEAREA 0.075 LAYER M3  ;
    ANTENNAMODEL OXIDE1 ;
    ANTENNAGATEAREA 0.6816 LAYER M3  ;
    ANTENNAMAXAREACAR 19.5212 LAYER M3  ;
    ANTENNAMAXSIDEAREACAR 0.202229 LAYER M3  ;
    ANTENNAMAXCUTCAR 2.29885 LAYER V3  ;
    PORT
      LAYER M3 ;
        RECT 0.000000 55.900000 0.600000 56.100000 ;
    END
  END SRAM_in_B_addr[6]
  PIN SRAM_in_B_addr[5]
    DIRECTION OUTPUT ;
    USE SIGNAL ;
    ANTENNAPARTIALMETALAREA 5.3 LAYER M3  ;
    ANTENNAPARTIALMETALSIDEAREA 0.0534 LAYER M3  ;
    ANTENNAMODEL OXIDE1 ;
    ANTENNAGATEAREA 0.5208 LAYER M3  ;
    ANTENNAMAXAREACAR 26.6761 LAYER M3  ;
    ANTENNAMAXSIDEAREACAR 0.26982 LAYER M3  ;
    ANTENNAPARTIALCUTAREA 0.08 LAYER V3  ;
    ANTENNAMAXCUTCAR 2.03564 LAYER V3  ;
    ANTENNADIFFAREA 2.014 LAYER M4  ;
    ANTENNAPARTIALMETALAREA 0.76 LAYER M4  ;
    ANTENNAPARTIALMETALSIDEAREA 0.008 LAYER M4  ;
    ANTENNAGATEAREA 0.6504 LAYER M4  ;
    ANTENNAMAXAREACAR 27.8446 LAYER M4  ;
    ANTENNAMAXSIDEAREACAR 0.28212 LAYER M4  ;
    ANTENNAMAXCUTCAR 2.16049 LAYER V4  ;
    PORT
      LAYER M3 ;
        RECT 0.000000 49.900000 0.600000 50.100000 ;
    END
  END SRAM_in_B_addr[5]
  PIN SRAM_in_B_addr[4]
    DIRECTION OUTPUT ;
    USE SIGNAL ;
    ANTENNADIFFAREA 2.014 LAYER M3  ;
    ANTENNAPARTIALMETALAREA 5.42 LAYER M3  ;
    ANTENNAPARTIALMETALSIDEAREA 0.055 LAYER M3  ;
    ANTENNAMODEL OXIDE1 ;
    ANTENNAGATEAREA 0.5064 LAYER M3  ;
    ANTENNAMAXAREACAR 23.1858 LAYER M3  ;
    ANTENNAMAXSIDEAREACAR 0.239644 LAYER M3  ;
    ANTENNAMAXCUTCAR 2.29885 LAYER V3  ;
    PORT
      LAYER M3 ;
        RECT 0.000000 43.900000 0.600000 44.100000 ;
    END
  END SRAM_in_B_addr[4]
  PIN SRAM_in_B_addr[3]
    DIRECTION OUTPUT ;
    USE SIGNAL ;
    ANTENNADIFFAREA 2.014 LAYER M3  ;
    ANTENNAPARTIALMETALAREA 6.06 LAYER M3  ;
    ANTENNAPARTIALMETALSIDEAREA 0.0614 LAYER M3  ;
    ANTENNAMODEL OXIDE1 ;
    ANTENNAGATEAREA 0.4272 LAYER M3  ;
    ANTENNAMAXAREACAR 20.921 LAYER M3  ;
    ANTENNAMAXSIDEAREACAR 0.21729 LAYER M3  ;
    ANTENNAMAXCUTCAR 2.29885 LAYER V3  ;
    PORT
      LAYER M3 ;
        RECT 0.000000 37.900000 0.600000 38.100000 ;
    END
  END SRAM_in_B_addr[3]
  PIN SRAM_in_B_addr[2]
    DIRECTION OUTPUT ;
    USE SIGNAL ;
    ANTENNADIFFAREA 2.014 LAYER M3  ;
    ANTENNAPARTIALMETALAREA 5.02 LAYER M3  ;
    ANTENNAPARTIALMETALSIDEAREA 0.051 LAYER M3  ;
    ANTENNAMODEL OXIDE1 ;
    ANTENNAGATEAREA 1.0968 LAYER M3  ;
    ANTENNAMAXAREACAR 29.7034 LAYER M3  ;
    ANTENNAMAXSIDEAREACAR 0.30397 LAYER M3  ;
    ANTENNAMAXCUTCAR 3.44828 LAYER V3  ;
    PORT
      LAYER M3 ;
        RECT 0.000000 31.900000 0.600000 32.100000 ;
    END
  END SRAM_in_B_addr[2]
  PIN SRAM_in_B_addr[1]
    DIRECTION OUTPUT ;
    USE SIGNAL ;
    ANTENNADIFFAREA 2.014 LAYER M3  ;
    ANTENNAPARTIALMETALAREA 5.98 LAYER M3  ;
    ANTENNAPARTIALMETALSIDEAREA 0.0606 LAYER M3  ;
    ANTENNAMODEL OXIDE1 ;
    ANTENNAGATEAREA 1.056 LAYER M3  ;
    ANTENNAMAXAREACAR 18.3212 LAYER M3  ;
    ANTENNAMAXSIDEAREACAR 0.185973 LAYER M3  ;
    ANTENNAMAXCUTCAR 1.76671 LAYER V3  ;
    PORT
      LAYER M3 ;
        RECT 0.000000 25.900000 0.600000 26.100000 ;
    END
  END SRAM_in_B_addr[1]
  PIN SRAM_in_B_addr[0]
    DIRECTION OUTPUT ;
    USE SIGNAL ;
    ANTENNADIFFAREA 3.488 LAYER M3  ;
    ANTENNAPARTIALMETALAREA 11.26 LAYER M3  ;
    ANTENNAPARTIALMETALSIDEAREA 0.1134 LAYER M3  ;
    ANTENNAMODEL OXIDE1 ;
    ANTENNAGATEAREA 1.2096 LAYER M3  ;
    ANTENNAMAXAREACAR 44.4371 LAYER M3  ;
    ANTENNAMAXSIDEAREACAR 0.452083 LAYER M3  ;
    ANTENNAMAXCUTCAR 3.20513 LAYER V3  ;
    PORT
      LAYER M3 ;
        RECT 0.000000 20.300000 0.600000 20.500000 ;
    END
  END SRAM_in_B_addr[0]
  PIN SRAM_WENB1
    DIRECTION OUTPUT ;
    USE SIGNAL ;
    ANTENNAPARTIALMETALAREA 5.3 LAYER M3  ;
    ANTENNAPARTIALMETALSIDEAREA 0.0534 LAYER M3  ;
    ANTENNAMODEL OXIDE1 ;
    ANTENNAGATEAREA 0.1728 LAYER M3  ;
    ANTENNAMAXAREACAR 32.588 LAYER M3  ;
    ANTENNAMAXSIDEAREACAR 0.33125 LAYER M3  ;
    ANTENNAPARTIALCUTAREA 0.08 LAYER V3  ;
    ANTENNAMAXCUTCAR 1.15741 LAYER V3  ;
    ANTENNADIFFAREA 2.848 LAYER M4  ;
    ANTENNAPARTIALMETALAREA 2.44 LAYER M4  ;
    ANTENNAPARTIALMETALSIDEAREA 0.0248 LAYER M4  ;
    ANTENNAGATEAREA 0.1728 LAYER M4  ;
    ANTENNAMAXAREACAR 46.7083 LAYER M4  ;
    ANTENNAMAXSIDEAREACAR 0.474769 LAYER M4  ;
    ANTENNAMAXCUTCAR 1.15741 LAYER V4  ;
    PORT
      LAYER M3 ;
        RECT 0.000000 163.100000 0.600000 163.300000 ;
    END
  END SRAM_WENB1
  PIN SRAM_WENB2
    DIRECTION OUTPUT ;
    USE SIGNAL ;
    ANTENNADIFFAREA 2.848 LAYER M3  ;
    ANTENNAPARTIALMETALAREA 5.5 LAYER M3  ;
    ANTENNAPARTIALMETALSIDEAREA 0.055 LAYER M3  ;
    ANTENNAMODEL OXIDE1 ;
    ANTENNAGATEAREA 0.3456 LAYER M3  ;
    ANTENNAMAXAREACAR 22.6412 LAYER M3  ;
    ANTENNAMAXSIDEAREACAR 0.226042 LAYER M3  ;
    ANTENNAMAXCUTCAR 0.694444 LAYER V3  ;
    PORT
      LAYER M3 ;
        RECT 0.000000 157.100000 0.600000 157.300000 ;
    END
  END SRAM_WENB2
  PIN SRAM_WENB3
    DIRECTION OUTPUT ;
    USE SIGNAL ;
    ANTENNADIFFAREA 2.848 LAYER M3  ;
    ANTENNAPARTIALMETALAREA 5.24 LAYER M3  ;
    ANTENNAPARTIALMETALSIDEAREA 0.0528 LAYER M3  ;
    ANTENNAMODEL OXIDE1 ;
    ANTENNAGATEAREA 0.3456 LAYER M3  ;
    ANTENNAMAXAREACAR 22.1713 LAYER M3  ;
    ANTENNAMAXSIDEAREACAR 0.225926 LAYER M3  ;
    ANTENNAMAXCUTCAR 1.38889 LAYER V3  ;
    PORT
      LAYER M3 ;
        RECT 0.000000 151.100000 0.600000 151.300000 ;
    END
  END SRAM_WENB3
  PIN SRAM_WENB4
    DIRECTION OUTPUT ;
    USE SIGNAL ;
    ANTENNAPARTIALMETALAREA 5.06 LAYER M3  ;
    ANTENNAPARTIALMETALSIDEAREA 0.051 LAYER M3  ;
    ANTENNAMODEL OXIDE1 ;
    ANTENNAGATEAREA 0.1728 LAYER M3  ;
    ANTENNAMAXAREACAR 32.4213 LAYER M3  ;
    ANTENNAMAXSIDEAREACAR 0.327315 LAYER M3  ;
    ANTENNAPARTIALCUTAREA 0.08 LAYER V3  ;
    ANTENNAMAXCUTCAR 1.38889 LAYER V3  ;
    ANTENNADIFFAREA 2.848 LAYER M4  ;
    ANTENNAPARTIALMETALAREA 7.44 LAYER M4  ;
    ANTENNAPARTIALMETALSIDEAREA 0.0752 LAYER M4  ;
    ANTENNAGATEAREA 0.42 LAYER M4  ;
    ANTENNAMAXAREACAR 50.1356 LAYER M4  ;
    ANTENNAMAXSIDEAREACAR 0.506362 LAYER M4  ;
    ANTENNAMAXCUTCAR 2.68817 LAYER V4  ;
    PORT
      LAYER M3 ;
        RECT 0.000000 145.100000 0.600000 145.300000 ;
    END
  END SRAM_WENB4
  PIN VSS
    DIRECTION INOUT ;
    USE GROUND ;

# P/G power stripe data as pin
    PORT
      LAYER M4 ;
        RECT 56.000000 1.000000 58.000000 178.800000 ;
        RECT 26.000000 1.000000 28.000000 178.800000 ;
        RECT 1.000000 1.000000 3.000000 178.800000 ;
        RECT 116.000000 1.000000 118.000000 178.800000 ;
        RECT 86.000000 1.000000 88.000000 178.800000 ;
        RECT 146.000000 1.000000 148.000000 178.800000 ;
        RECT 176.000000 1.000000 178.000000 178.800000 ;
        RECT 206.000000 1.000000 208.000000 178.800000 ;
        RECT 237.000000 1.000000 239.000000 178.800000 ;
    END
# end of P/G power stripe data as pin

  END VSS
  PIN VDD
    DIRECTION INOUT ;
    USE POWER ;

# P/G power stripe data as pin
    PORT
      LAYER M4 ;
        RECT 52.000000 4.000000 54.000000 175.800000 ;
        RECT 22.000000 4.000000 24.000000 175.800000 ;
        RECT 4.000000 4.000000 6.000000 175.800000 ;
        RECT 112.000000 4.000000 114.000000 175.800000 ;
        RECT 82.000000 4.000000 84.000000 175.800000 ;
        RECT 142.000000 4.000000 144.000000 175.800000 ;
        RECT 172.000000 4.000000 174.000000 175.800000 ;
        RECT 202.000000 4.000000 204.000000 175.800000 ;
        RECT 234.000000 4.000000 236.000000 175.800000 ;
    END
# end of P/G power stripe data as pin

  END VDD
  OBS
    LAYER M1 ;
      RECT 0.000000 0.000000 240.000000 180.000000 ;
    LAYER M2 ;
      RECT 118.020000 177.480000 240.000000 180.000000 ;
      RECT 111.220000 177.480000 113.980000 180.000000 ;
      RECT 104.420000 177.480000 107.180000 180.000000 ;
      RECT 97.620000 177.480000 100.380000 180.000000 ;
      RECT 90.820000 177.480000 93.580000 180.000000 ;
      RECT 84.020000 177.480000 86.780000 180.000000 ;
      RECT 77.220000 177.480000 79.980000 180.000000 ;
      RECT 70.420000 177.480000 73.180000 180.000000 ;
      RECT 63.620000 177.480000 66.380000 180.000000 ;
      RECT 56.820000 177.480000 59.580000 180.000000 ;
      RECT 50.020000 177.480000 52.780000 180.000000 ;
      RECT 43.220000 177.480000 45.980000 180.000000 ;
      RECT 36.420000 177.480000 39.180000 180.000000 ;
      RECT 0.000000 177.480000 32.380000 180.000000 ;
      RECT 0.000000 2.520000 240.000000 177.480000 ;
      RECT 202.020000 0.000000 240.000000 2.520000 ;
      RECT 186.820000 0.000000 197.980000 2.520000 ;
      RECT 180.820000 0.000000 182.780000 2.520000 ;
      RECT 174.420000 0.000000 176.780000 2.520000 ;
      RECT 162.020000 0.000000 170.380000 2.520000 ;
      RECT 156.420000 0.000000 157.980000 2.520000 ;
      RECT 150.820000 0.000000 152.380000 2.520000 ;
      RECT 144.820000 0.000000 146.780000 2.520000 ;
      RECT 124.820000 0.000000 140.780000 2.520000 ;
      RECT 117.220000 0.000000 120.780000 2.520000 ;
      RECT 109.220000 0.000000 113.180000 2.520000 ;
      RECT 101.620000 0.000000 105.180000 2.520000 ;
      RECT 93.620000 0.000000 97.580000 2.520000 ;
      RECT 86.020000 0.000000 89.580000 2.520000 ;
      RECT 78.020000 0.000000 81.980000 2.520000 ;
      RECT 70.020000 0.000000 73.980000 2.520000 ;
      RECT 0.000000 0.000000 65.980000 2.520000 ;
    LAYER M3 ;
      RECT 0.000000 165.220000 240.000000 180.000000 ;
      RECT 2.520000 161.180000 240.000000 165.220000 ;
      RECT 0.000000 159.220000 240.000000 161.180000 ;
      RECT 2.520000 155.180000 240.000000 159.220000 ;
      RECT 0.000000 153.220000 240.000000 155.180000 ;
      RECT 2.520000 149.180000 240.000000 153.220000 ;
      RECT 0.000000 147.220000 240.000000 149.180000 ;
      RECT 2.520000 143.180000 240.000000 147.220000 ;
      RECT 0.000000 142.020000 240.000000 143.180000 ;
      RECT 0.000000 141.220000 237.480000 142.020000 ;
      RECT 2.520000 137.980000 237.480000 141.220000 ;
      RECT 2.520000 137.180000 240.000000 137.980000 ;
      RECT 0.000000 135.220000 240.000000 137.180000 ;
      RECT 2.520000 131.180000 240.000000 135.220000 ;
      RECT 0.000000 129.220000 240.000000 131.180000 ;
      RECT 2.520000 125.180000 240.000000 129.220000 ;
      RECT 0.000000 123.220000 240.000000 125.180000 ;
      RECT 2.520000 119.180000 240.000000 123.220000 ;
      RECT 0.000000 117.220000 240.000000 119.180000 ;
      RECT 2.520000 113.180000 240.000000 117.220000 ;
      RECT 0.000000 110.820000 240.000000 113.180000 ;
      RECT 2.520000 106.780000 240.000000 110.820000 ;
      RECT 0.000000 104.820000 240.000000 106.780000 ;
      RECT 2.520000 100.780000 240.000000 104.820000 ;
      RECT 0.000000 98.820000 240.000000 100.780000 ;
      RECT 2.520000 94.780000 240.000000 98.820000 ;
      RECT 0.000000 92.820000 240.000000 94.780000 ;
      RECT 2.520000 88.780000 240.000000 92.820000 ;
      RECT 0.000000 86.420000 240.000000 88.780000 ;
      RECT 2.520000 82.380000 240.000000 86.420000 ;
      RECT 0.000000 82.020000 240.000000 82.380000 ;
      RECT 0.000000 77.980000 237.480000 82.020000 ;
      RECT 0.000000 76.020000 240.000000 77.980000 ;
      RECT 2.520000 71.980000 240.000000 76.020000 ;
      RECT 0.000000 70.020000 240.000000 71.980000 ;
      RECT 2.520000 65.980000 240.000000 70.020000 ;
      RECT 0.000000 64.020000 240.000000 65.980000 ;
      RECT 2.520000 59.980000 240.000000 64.020000 ;
      RECT 0.000000 58.020000 240.000000 59.980000 ;
      RECT 2.520000 53.980000 240.000000 58.020000 ;
      RECT 0.000000 52.020000 240.000000 53.980000 ;
      RECT 2.520000 47.980000 240.000000 52.020000 ;
      RECT 0.000000 46.020000 240.000000 47.980000 ;
      RECT 2.520000 41.980000 240.000000 46.020000 ;
      RECT 0.000000 40.020000 240.000000 41.980000 ;
      RECT 2.520000 35.980000 240.000000 40.020000 ;
      RECT 0.000000 34.020000 240.000000 35.980000 ;
      RECT 2.520000 29.980000 240.000000 34.020000 ;
      RECT 0.000000 28.020000 240.000000 29.980000 ;
      RECT 2.520000 23.980000 240.000000 28.020000 ;
      RECT 0.000000 22.420000 240.000000 23.980000 ;
      RECT 2.520000 18.380000 240.000000 22.420000 ;
      RECT 0.000000 0.000000 240.000000 18.380000 ;
    LAYER M4 ;
      RECT 209.920000 177.720000 235.080000 180.000000 ;
      RECT 179.920000 177.720000 204.080000 180.000000 ;
      RECT 149.920000 177.720000 174.080000 180.000000 ;
      RECT 119.920000 177.720000 144.080000 180.000000 ;
      RECT 89.920000 177.720000 114.080000 180.000000 ;
      RECT 59.920000 177.720000 84.080000 180.000000 ;
      RECT 29.920000 177.720000 54.080000 180.000000 ;
      RECT 4.920000 177.720000 24.080000 180.000000 ;
      RECT 209.920000 2.080000 232.080000 177.720000 ;
      RECT 179.920000 2.080000 200.080000 177.720000 ;
      RECT 149.920000 2.080000 170.080000 177.720000 ;
      RECT 119.920000 2.080000 140.080000 177.720000 ;
      RECT 89.920000 2.080000 110.080000 177.720000 ;
      RECT 59.920000 2.080000 80.080000 177.720000 ;
      RECT 29.920000 2.080000 50.080000 177.720000 ;
      RECT 7.920000 2.080000 20.080000 177.720000 ;
      RECT 209.920000 0.000000 235.080000 2.080000 ;
      RECT 179.920000 0.000000 204.080000 2.080000 ;
      RECT 149.920000 0.000000 174.080000 2.080000 ;
      RECT 119.920000 0.000000 144.080000 2.080000 ;
      RECT 89.920000 0.000000 114.080000 2.080000 ;
      RECT 59.920000 0.000000 84.080000 2.080000 ;
      RECT 29.920000 0.000000 54.080000 2.080000 ;
      RECT 4.920000 0.000000 24.080000 2.080000 ;
  END
END Main_controller

END LIBRARY
